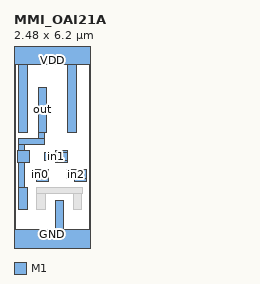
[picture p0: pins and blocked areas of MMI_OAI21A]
MACRO MMI_OAI21A
	CLASS CORE ;
	FOREIGN MMI_OAI21A 0 0 ;
	SIZE 2.48 BY 6.2 ;
	SYMMETRY X Y ;
	SITE CORE1 ;
	PIN out
		DIRECTION output ;
		USE SIGNAL ;
		PORT
			LAYER M1 ;
			RECT 0.795 3.585 1.075 5.055 ;
			LAYER M1 ;
			RECT 0.795 3.385 0.985 3.585 ;
			LAYER M1 ;
			RECT 0.16 3.19 0.985 3.385 ;
			LAYER M1 ;
			RECT 0.16 2.98 0.355 3.19 ;
			LAYER M1 ;
			RECT 0.12 2.6 0.5 2.98 ;
			LAYER M1 ;
			RECT 0.16 1.765 0.355 2.6 ;
			LAYER M1 ;
			RECT 0.16 1.065 0.44 1.765 ;
		END
		AntennaDiffArea 0.98175 ;
	END out
	PIN in1
		DIRECTION input ;
		USE SIGNAL ;
		PORT
			LAYER M1 ;
			RECT 1.36 2.935 1.74 2.98 ;
			LAYER M1 ;
			RECT 1.11 2.93 1.74 2.935 ;
			LAYER M1 ;
			RECT 0.99 2.65 1.74 2.93 ;
			LAYER M1 ;
			RECT 1.36 2.6 1.74 2.65 ;
		END
		AntennaGateArea 0.3465 ;
	END in1
	PIN GND
		DIRECTION inout ;
		USE GROUND ;
		PORT
			LAYER M1 ;
			RECT 1.34 0.42 1.62 1.345 ;
			LAYER M1 ;
			RECT 0 -0.42 2.48 0.42 ;
		END
	END GND
	PIN in2
		DIRECTION input ;
		USE SIGNAL ;
		PORT
			LAYER M1 ;
			RECT 1.98 2.35 2.36 2.36 ;
			LAYER M1 ;
			RECT 1.7 2.07 2.36 2.35 ;
			LAYER M1 ;
			RECT 1.98 1.98 2.36 2.07 ;
		END
		AntennaGateArea 0.3465 ;
	END in2
	PIN VDD
		DIRECTION inout ;
		USE POWER ;
		PORT
			LAYER M1 ;
			RECT 0 5.78 2.48 6.62 ;
			LAYER M1 ;
			RECT 0.16 3.585 0.44 5.78 ;
			LAYER M1 ;
			RECT 1.755 3.585 2.035 5.78 ;
		END
	END VDD
	PIN in0
		DIRECTION input ;
		USE SIGNAL ;
		PORT
			LAYER M1 ;
			RECT 0.74 2.355 1.12 2.36 ;
			LAYER M1 ;
			RECT 0.555 2.075 1.12 2.355 ;
			LAYER M1 ;
			RECT 0.74 1.98 1.12 2.075 ;
		END
		AntennaGateArea 0.231 ;
	END in0
	OBS
		LAYER M1 ;
		RECT 0.755 1.765 2.245 1.77 ;
		LAYER M1 ;
		RECT 0.75 1.575 2.245 1.765 ;
		LAYER M1 ;
		RECT 0.75 1.065 1.03 1.575 ;
		LAYER M1 ;
		RECT 1.93 1.065 2.21 1.575 ;
	END
END MMI_OAI21A
